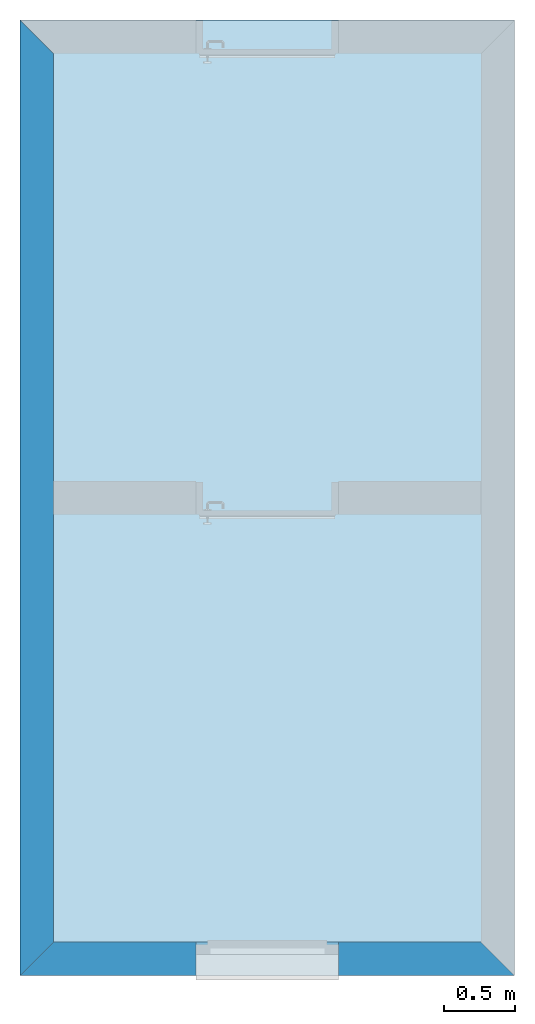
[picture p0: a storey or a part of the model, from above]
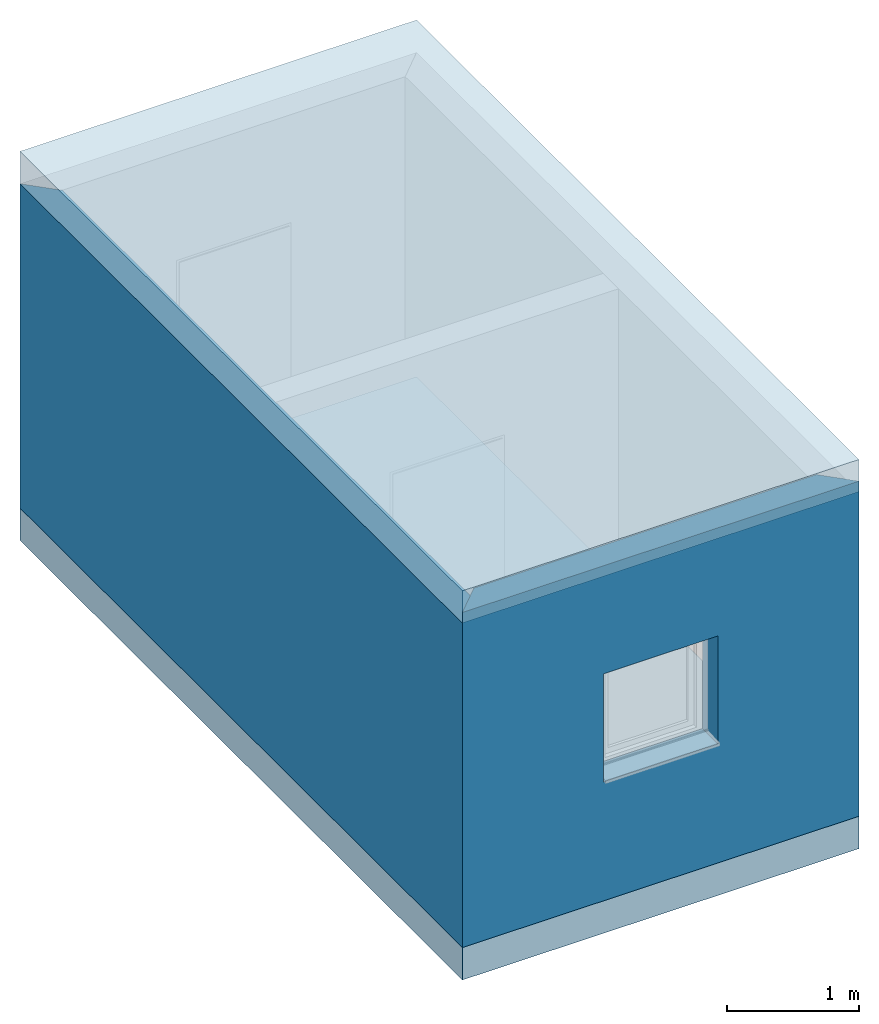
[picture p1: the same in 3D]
Properties of the parts of a building model (IFC2X3)

# File
Description: ViewDefinition [CoordinationView_V2.0, SpaceBoundary2ndLevelAddOnView], Option [Drawing Scale: 100.000000], Option [Global Unique Identifiers (GUID): Keep existing], Option [Elements to export: Selected elements only], Option [Partial Structure Display: Entire Model], Option [IFC Domain: All], Option [Structural Function: All Elements], Option [Convert Grid elements: On], Option [Convert IFC Annotations and ArchiCAD 2D elements: Off], Option [Convert 2D symbols of Doors and Windows: Off], Option [Explode Composite and Complex Profile elements into parts: Off], Option [Export geometries that Participates in Collision Detection only: On], Option [Multi-skin complex geometries: Building element parts], Option [Elements in Solid Element Operations: Extruded/revolved], Option [Elements with junctions: Extruded/revolved without junctions], Option [Slabs with slanted edge(s): Extruded], Option [Use legacy geometric methods as in Coordination View 1.0: Off], Option [IFC Site Geometry: As boundary representation (BRep)], Option [Properties To Export: All properties], Option [Space containment: Off], Option [Bounding Box: Off], Option [Geometry to type objects: Off], Option [IFC base quantities (size, area and volume): Off], Option [All ArchiCAD BIM parameters: Off], Option [IFC Space boundaries: On], Option [ArchiCAD Zone Categories as IFC Space classification data: Off]
File name: TwoZones.ifc
Time: 2016-10-16T22:59:57
Author: Architect
Organization: Building Designer Office
Written by: PreProc - EDM 5.0
Made in: IFC file generated by Graphisoft ArchiCAD-64 18.0.0 CHE FULL Macintosh version (IFC2x3 add-on version: 4034 CHE FULL).
Authorization: The authorising person

# IfcSite, Gelände
RefLatitude: 46, 54, 0, 0; RefLongitude: 8, 15, 0, 0; RefElevation: 473000 mm

# IfcBuildingStorey, TowZone
In: Gebäude
Elevation: 3100 mm

# IfcSpace: Hauptnutzfläche (2)
In: TowZone
LongName: WOHNEN; InteriorOrExteriorSpace: INTERNAL
AC_Pset_RenovationAndPhasing - Renovation Status: Existing

# IfcDoor: Eingangstür 18 (2)
In: TowZone
Type - OperationType: SINGLE_SWING_LEFT; ParameterTakesPrecedence: no; Sizeable: no
OverallHeight: 2000 mm; OverallWidth: 1000 mm
AC_Pset_RenovationAndPhasing - Renovation Status: Existing

# IfcSlab: Allgemein, Konstruktion 300 (2)
In: TowZone
Type - PredefinedType: FLOOR
Material: Allgemein, Konstruktion 300 mm
AC_Pset_RenovationAndPhasing - Renovation Status: Existing

# IfcWallStandardCase: OneZone 235 (5)
In: TowZone
Material: Verputz, Innen 15 mm, Beton, Stahlbeton 200 mm, Verputz, Aussen 20 mm
AC_Pset_RenovationAndPhasing - Renovation Status: Existing

# IfcWindow: 1-Flügelfenster 18, Fenster-001
In: TowZone
Type - OperationType: SINGLE_PANEL; ParameterTakesPrecedence: no; Sizeable: no
OverallHeight: 1000 mm; OverallWidth: 1000 mm
AC_Pset_RenovationAndPhasing - Renovation Status: Existing
